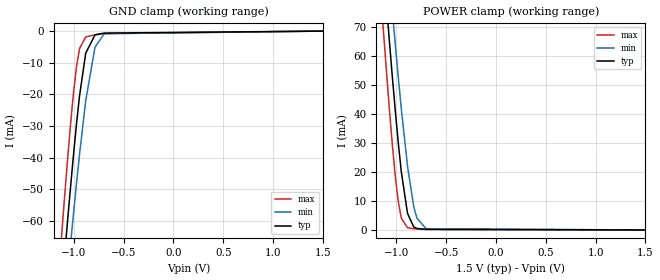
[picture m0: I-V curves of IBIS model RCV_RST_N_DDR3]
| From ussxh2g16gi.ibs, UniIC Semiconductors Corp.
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|   Model RCV_RST_N_DDR3
[Model] RCV_RST_N_DDR3
Model_type Input
Vinl =  0.615V
Vinh =  0.885V
C_comp   0.725pF   0.725pF   0.725pF
[Model Spec]
Vinh   0.885V   0.847V   0.922V
Vinl   0.615V   0.577V   0.652V
[Temperature Range]   25.000   95.000   -40.000
[Voltage Range]   1.500V   1.425V   1.575V
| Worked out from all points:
|   GND clamp passes 1 mA (typ) near -0.77 V on its own axis
|   POWER clamp passes 1 mA (typ) near -0.82 V on its own axis
[GND_clamp]
|Voltage   I(typ)   I(min)   I(max)
-1.5V     -234.6mA   -235.5mA   -234.8mA
-1.128V   -84.6mA    -99.98mA   -67.29mA
-1.097V   -72.88mA   -89.25mA   -54.45mA
-1.066V   -61.4mA    -78.68mA   -42.08mA
-1.035V   -50.27mA   -68.31mA   -30.45mA
-1.004V   -39.59mA   -58.18mA   -19.95mA
-973mV    -29.55mA   -48.37mA   -11.32mA
-942mV    -20.46mA   -38.97mA   -5.526mA
-880mV    -6.992mA   -22.01mA   -1.849mA
-787mV    -1.189mA   -5.118mA   -1.177mA
-694mV    -640.7uA   -822.5uA   -788.2uA
1.5V      0A         0A         0A
[POWER_clamp]
|Voltage   I(typ)   I(min)   I(max)
-1.5V     266.1mA    275.5mA    256.6mA
-1.135V   93.87mA    114.7mA    71.48mA
-1.073V   66.81mA    89.06mA    43.3mA
-1.042V   53.9mA     76.59mA    30.42mA
-1.011V   41.59mA    64.46mA    18.97mA
-980mV    30.14mA    52.76mA    9.83mA
-949mV    19.96mA    41.64mA    4.037mA
-887mV    5.735mA    22mA       744.4uA
-825mV    1.051mA    8.135mA    425.3uA
-794mV    525.1uA    4.165mA    366.5uA
-701mV    192.8uA    447uA      227.2uA
1.5V      0A         0A         0A
